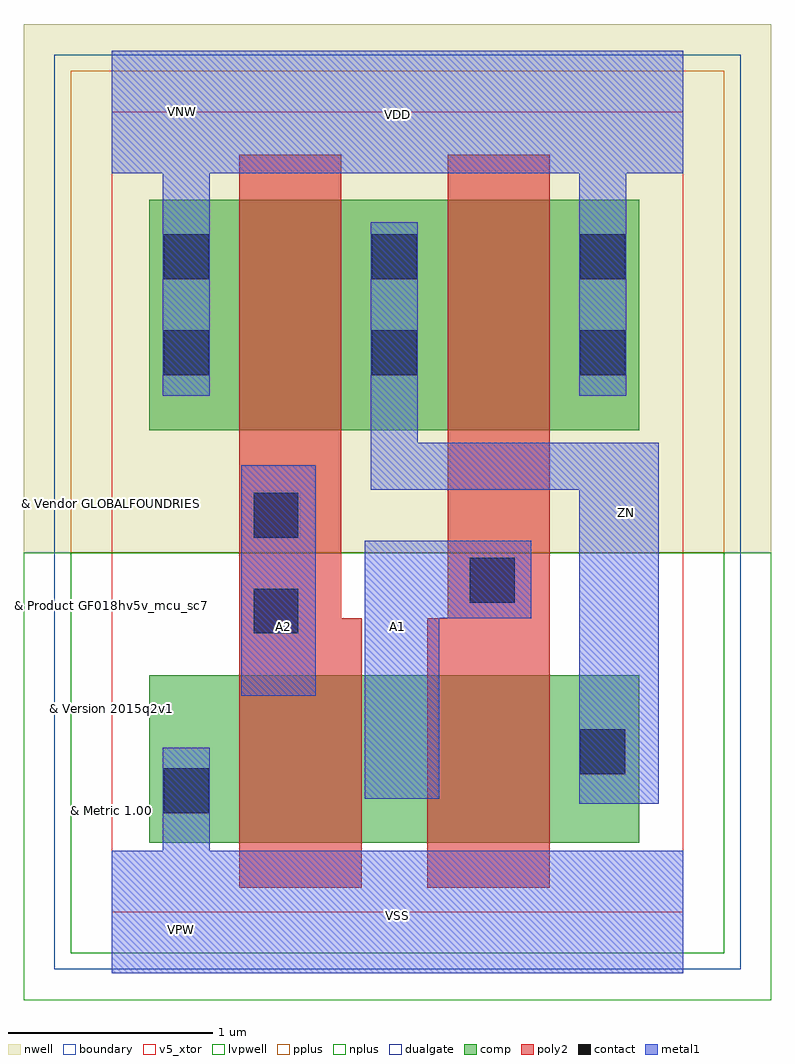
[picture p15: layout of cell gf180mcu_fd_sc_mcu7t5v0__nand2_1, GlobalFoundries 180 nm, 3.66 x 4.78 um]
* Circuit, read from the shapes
.subckt gf180mcu_fd_sc_mcu7t5v0__nand2_1 A1 A2 VDD VNW VSS ZN
XM1 n1 A2 VSS VSUBS nfet_05v0 w=0.82u l=0.6u
XM2 ZN A1 n1 VSUBS nfet_05v0 w=0.82u l=0.6u
XM3 ZN A2 VDD VNW pfet_05v0 w=1.13u l=0.5u
XM4 VDD A1 ZN VNW pfet_05v0 w=1.13u l=0.5u
.ends

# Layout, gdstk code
import gdstk
lib = gdstk.Library(unit=1e-6, precision=1e-09)
def R(c, l, rs):  # rectangles x0, y0, x1, y1
    for r in rs: c.add(gdstk.rectangle(r[:2], r[2:], *l))
def A(c, l, x, y, w, h, nx, ny, dx, dy):  # array of equal rectangles
    R(c, l, [(x+i*dx, y+j*dy, x+i*dx+w, y+j*dy+h) for i in range(nx) for j in range(ny)])
def P(c, l, *ps):  # polygons
    for p in ps: c.add(gdstk.Polygon(p, *l))
boundary = (0, 0)
nwell = (21, 0)
comp = (22, 0)
poly2 = (30, 0)
pplus = (31, 0)
nplus = (32, 0)
contact = (33, 0)
metal1 = (34, 0)
dualgate = (55, 0)
v5_xtor = (112, 1)
lvpwell = (204, 0)

gf180mcu_fd_sc_mcu7t5v0_ = lib.new_cell('gf180mcu_fd_sc_mcu7t5v0__nand2_1')
R(gf180mcu_fd_sc_mcu7t5v0_, boundary, [(0,0,2.8,3.92)])
R(gf180mcu_fd_sc_mcu7t5v0_, nwell, [(-0.43,1.76,3.23,4.35)])
R(gf180mcu_fd_sc_mcu7t5v0_, comp, [(0.185,0.34,2.585,1.16), (0.185,2.36,2.585,3.49)])
P(gf180mcu_fd_sc_mcu7t5v0_, poly2, [(0.625,0.12),(0.625,3.71),(1.125,3.71),(1.125,1.44),(1.225,1.44),(1.225,0.12)],
  [(1.545,0.12),(1.545,1.44),(1.645,1.44),(1.645,3.71),(2.145,3.71),(2.145,0.12)])
R(gf180mcu_fd_sc_mcu7t5v0_, pplus, [(-0.2,1.76,3,4.12)])
R(gf180mcu_fd_sc_mcu7t5v0_, nplus, [(-0.2,-0.2,3,1.76)])
A(gf180mcu_fd_sc_mcu7t5v0_, contact, 0.255, 2.63, 0.22, 0.22, 3, 2, 1.02, 0.47)
R(gf180mcu_fd_sc_mcu7t5v0_, contact, [(0.255,0.485,0.475,0.705), (2.295,0.675,2.515,0.895), (0.695,1.365,0.915,1.585), (1.755,1.515,1.975,1.735), (0.695,1.835,0.915,2.055)])
R(gf180mcu_fd_sc_mcu7t5v0_, metal1, [(0.635,1.06,1,2.19)])
P(gf180mcu_fd_sc_mcu7t5v0_, metal1, [(1.24,0.555),(1.24,1.82),(2.055,1.82),(2.055,1.44),(1.605,1.44),(1.605,0.555)],
  [(2.29,0.53),(2.29,2.07),(1.27,2.07),(1.27,3.38),(1.5,3.38),(1.5,2.3),(2.68,2.3),(2.68,0.53)],
  [(0,-0.3),(0,0.3),(0.25,0.3),(0.25,0.805),(0.48,0.805),(0.48,0.3),(2.8,0.3),(2.8,-0.3)],
  [(0.25,2.53),(0.25,3.62),(0,3.62),(0,4.22),(2.8,4.22),(2.8,3.62),(2.52,3.62),(2.52,2.53),(2.29,2.53),(2.29,3.62),(0.48,3.62),(0.48,2.53)])
R(gf180mcu_fd_sc_mcu7t5v0_, dualgate, [(-0.28,-0.28,3.08,4.2)])
R(gf180mcu_fd_sc_mcu7t5v0_, v5_xtor, [(0,0,2.8,3.92)])
R(gf180mcu_fd_sc_mcu7t5v0_, lvpwell, [(-0.43,-0.43,3.23,1.76)])
gf180mcu_fd_sc_mcu7t5v0_.add(gdstk.Label('VDD', (1.4,3.905), layer=34, texttype=10))
gf180mcu_fd_sc_mcu7t5v0_.add(gdstk.Label('VSS', (1.4,-0.015), layer=34, texttype=10))
gf180mcu_fd_sc_mcu7t5v0_.add(gdstk.Label('ZN', (2.52,1.96), layer=34, texttype=10))
gf180mcu_fd_sc_mcu7t5v0_.add(gdstk.Label('A1', (1.4,1.4), layer=34, texttype=10))
gf180mcu_fd_sc_mcu7t5v0_.add(gdstk.Label('A2', (0.84,1.4), layer=34, texttype=10))
gf180mcu_fd_sc_mcu7t5v0_.add(gdstk.Label('& Vendor GLOBALFOUNDRIES', (0,2), layer=63, texttype=63))
gf180mcu_fd_sc_mcu7t5v0_.add(gdstk.Label('& Product GF018hv5v_mcu_sc7', (0,1.5), layer=63, texttype=63))
gf180mcu_fd_sc_mcu7t5v0_.add(gdstk.Label('& Version 2015q2v1', (0,1), layer=63, texttype=63))
gf180mcu_fd_sc_mcu7t5v0_.add(gdstk.Label('& Metric 1.00', (0,0.5), layer=63, texttype=63))
gf180mcu_fd_sc_mcu7t5v0_.add(gdstk.Label('VNW', (0.345,3.92), layer=21, texttype=10))
gf180mcu_fd_sc_mcu7t5v0_.add(gdstk.Label('VPW', (0.34,-0.085), layer=204, texttype=10))

lib.write_gds('gf180mcu_fd_sc_mcu7t5v0__nand2_1.gds')
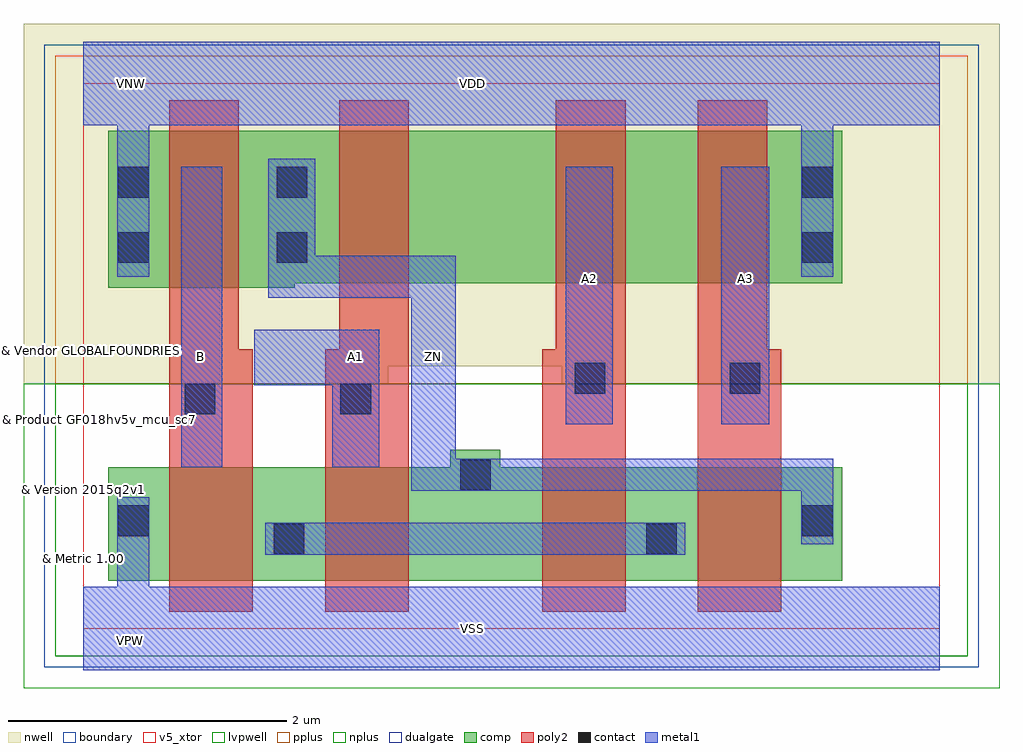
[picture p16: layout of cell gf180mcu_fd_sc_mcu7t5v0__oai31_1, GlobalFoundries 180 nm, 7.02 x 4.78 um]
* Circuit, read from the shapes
.subckt gf180mcu_fd_sc_mcu7t5v0__oai31_1 A1 A2 A3 B VDD VNW VSS ZN
XM1 n1 B VSS VSUBS nfet_05v0 w=0.815u l=0.6u
XM2 ZN A1 n1 VSUBS nfet_05v0 w=0.815u l=0.6u
XM3 n1 A2 ZN VSUBS nfet_05v0 w=0.815u l=0.6u
XM4 ZN A3 n1 VSUBS nfet_05v0 w=0.815u l=0.6u
XM5 ZN B VDD VNW pfet_05v0 w=1.13u l=0.5u
XM6 n2 A1 ZN VNW pfet_05v0 w=1.095u l=0.5u
XM7 n3 A2 n2 VNW pfet_05v0 w=1.095u l=0.5u
XM8 VDD A3 n3 VNW pfet_05v0 w=1.095u l=0.5u
.ends

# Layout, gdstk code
import gdstk
lib = gdstk.Library(unit=1e-6, precision=1e-09)
def R(c, l, rs):  # rectangles x0, y0, x1, y1
    for r in rs: c.add(gdstk.rectangle(r[:2], r[2:], *l))
def P(c, l, *ps):  # polygons
    for p in ps: c.add(gdstk.Polygon(p, *l))
boundary = (0, 0)
nwell = (21, 0)
comp = (22, 0)
poly2 = (30, 0)
pplus = (31, 0)
nplus = (32, 0)
contact = (33, 0)
metal1 = (34, 0)
dualgate = (55, 0)
v5_xtor = (112, 1)
lvpwell = (204, 0)

gf180mcu_fd_sc_mcu7t5v0_ = lib.new_cell('gf180mcu_fd_sc_mcu7t5v0__oai31_1')
R(gf180mcu_fd_sc_mcu7t5v0_, boundary, [(0,0,6.16,3.92)])
P(gf180mcu_fd_sc_mcu7t5v0_, nwell, [(-0.43,1.76),(-0.43,4.35),(6.59,4.35),(6.59,1.76),(3.44,1.76),(3.44,1.885),(2.195,1.885),(2.195,1.76)])
P(gf180mcu_fd_sc_mcu7t5v0_, comp, [(0.18,0.345),(0.18,1.16),(2.64,1.16),(2.64,1.285),(3,1.285),(3,1.16),(5.46,1.16),(5.46,0.345)],
  [(0.18,2.45),(0.18,3.58),(5.46,3.58),(5.46,2.485),(1.52,2.485),(1.52,2.45)])
P(gf180mcu_fd_sc_mcu7t5v0_, poly2, [(0.62,0.12),(0.62,3.8),(1.12,3.8),(1.12,2.01),(1.22,2.01),(1.22,0.12)],
  [(1.74,0.12),(1.74,2.01),(1.84,2.01),(1.84,3.8),(2.34,3.8),(2.34,0.12)],
  [(3.3,0.12),(3.3,2.01),(3.4,2.01),(3.4,3.8),(3.9,3.8),(3.9,0.12)],
  [(4.42,0.12),(4.42,3.8),(4.92,3.8),(4.92,2.01),(5.02,2.01),(5.02,0.12)])
R(gf180mcu_fd_sc_mcu7t5v0_, pplus, [(-0.2,1.76,6.36,4.12)])
R(gf180mcu_fd_sc_mcu7t5v0_, nplus, [(-0.2,-0.2,6.36,1.76)])
R(gf180mcu_fd_sc_mcu7t5v0_, contact, [(1.37,0.535,1.59,0.755), (4.05,0.535,4.27,0.755), (0.25,0.665,0.47,0.885), (5.17,0.665,5.39,0.885), (2.71,0.995,2.93,1.215), (0.73,1.54,0.95,1.76), (1.85,1.54,2.07,1.76), (3.535,1.69,3.755,1.91), (4.65,1.69,4.87,1.91), (0.25,2.63,0.47,2.85), (1.39,2.63,1.61,2.85), (5.17,2.63,5.39,2.85), (0.25,3.1,0.47,3.32), (1.39,3.1,1.61,3.32), (5.17,3.1,5.39,3.32)])
R(gf180mcu_fd_sc_mcu7t5v0_, metal1, [(1.31,0.53,4.33,0.76), (0.705,1.16,1,3.32), (3.47,1.47,3.81,3.32), (4.59,1.47,4.935,3.32)])
P(gf180mcu_fd_sc_mcu7t5v0_, metal1, [(1.79,1.16),(1.79,1.75),(1.23,1.75),(1.23,2.15),(2.13,2.15),(2.13,1.16)],
  [(5.165,0.605),(5.165,0.99),(2.36,0.99),(2.36,2.38),(1.33,2.38),(1.33,3.38),(1.67,3.38),(1.67,2.68),(2.68,2.68),(2.68,1.22),(5.395,1.22),(5.395,0.605)],
  [(0,-0.3),(0,0.3),(0.245,0.3),(0.245,0.945),(0.475,0.945),(0.475,0.3),(6.16,0.3),(6.16,-0.3)],
  [(0.245,2.53),(0.245,3.62),(0,3.62),(0,4.22),(6.16,4.22),(6.16,3.62),(5.395,3.62),(5.395,2.53),(5.165,2.53),(5.165,3.62),(0.475,3.62),(0.475,2.53)])
R(gf180mcu_fd_sc_mcu7t5v0_, dualgate, [(-0.28,-0.28,6.44,4.2)])
R(gf180mcu_fd_sc_mcu7t5v0_, v5_xtor, [(0,0,6.16,3.92)])
R(gf180mcu_fd_sc_mcu7t5v0_, lvpwell, [(-0.43,-0.43,6.59,1.76)])
gf180mcu_fd_sc_mcu7t5v0_.add(gdstk.Label('VDD', (2.8,3.92), layer=34, texttype=10))
gf180mcu_fd_sc_mcu7t5v0_.add(gdstk.Label('ZN', (2.52,1.96), layer=34, texttype=10))
gf180mcu_fd_sc_mcu7t5v0_.add(gdstk.Label('B', (0.84,1.96), layer=34, texttype=10))
gf180mcu_fd_sc_mcu7t5v0_.add(gdstk.Label('A1', (1.96,1.96), layer=34, texttype=10))
gf180mcu_fd_sc_mcu7t5v0_.add(gdstk.Label('A2', (3.64,2.52), layer=34, texttype=10))
gf180mcu_fd_sc_mcu7t5v0_.add(gdstk.Label('VSS', (2.8,0), layer=34, texttype=10))
gf180mcu_fd_sc_mcu7t5v0_.add(gdstk.Label('A3', (4.76,2.52), layer=34, texttype=10))
gf180mcu_fd_sc_mcu7t5v0_.add(gdstk.Label('& Vendor GLOBALFOUNDRIES', (0,2), layer=63, texttype=63))
gf180mcu_fd_sc_mcu7t5v0_.add(gdstk.Label('& Product GF018hv5v_mcu_sc7', (0,1.5), layer=63, texttype=63))
gf180mcu_fd_sc_mcu7t5v0_.add(gdstk.Label('& Version 2015q2v1', (0,1), layer=63, texttype=63))
gf180mcu_fd_sc_mcu7t5v0_.add(gdstk.Label('& Metric 1.00', (0,0.5), layer=63, texttype=63))
gf180mcu_fd_sc_mcu7t5v0_.add(gdstk.Label('VNW', (0.345,3.92), layer=21, texttype=10))
gf180mcu_fd_sc_mcu7t5v0_.add(gdstk.Label('VPW', (0.34,-0.085), layer=204, texttype=10))

lib.write_gds('gf180mcu_fd_sc_mcu7t5v0__oai31_1.gds')
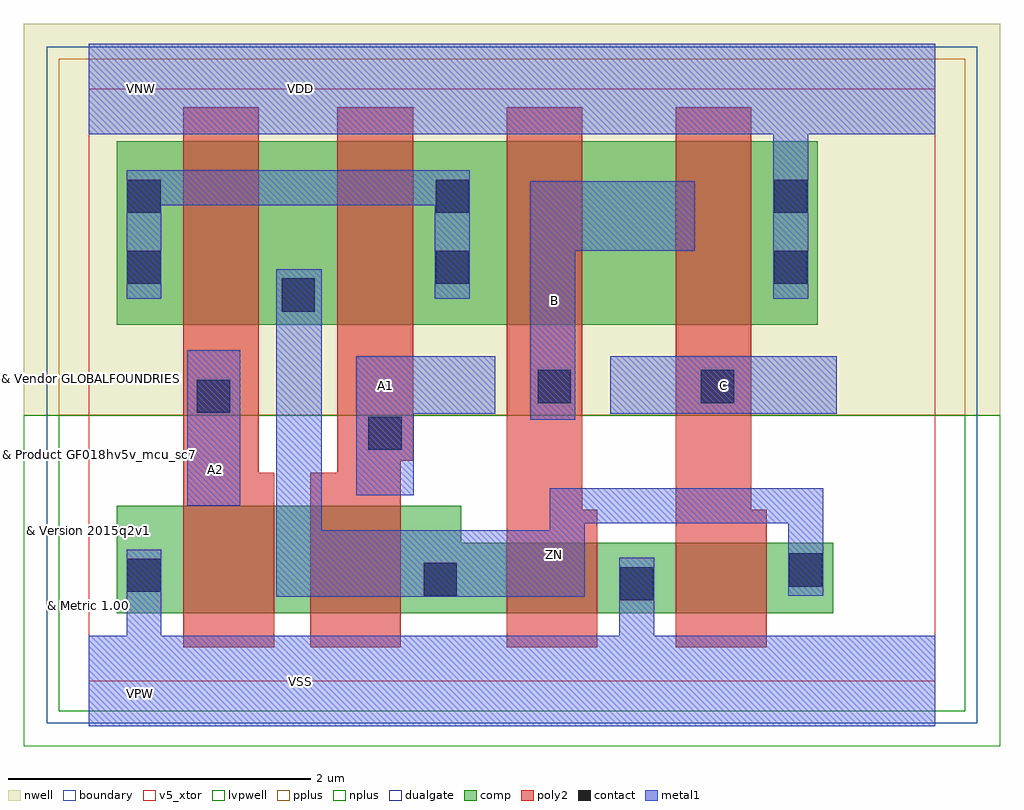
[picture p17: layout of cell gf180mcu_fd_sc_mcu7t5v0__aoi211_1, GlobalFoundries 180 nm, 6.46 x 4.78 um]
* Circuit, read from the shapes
.subckt gf180mcu_fd_sc_mcu7t5v0__aoi211_1 A1 A2 B C VDD VNW VSS ZN
XM1 n1 A2 VSS VSUBS nfet_05v0 w=0.71u l=0.6u
XM2 ZN A1 n1 VSUBS nfet_05v0 w=0.71u l=0.6u
XM3 VSS B ZN VSUBS nfet_05v0 w=0.465u l=0.6u
XM4 ZN C VSS VSUBS nfet_05v0 w=0.465u l=0.6u
XM5 ZN A2 n2 VNW pfet_05v0 w=1.215u l=0.5u
XM6 n2 A1 ZN VNW pfet_05v0 w=1.215u l=0.5u
XM7 n3 B n2 VNW pfet_05v0 w=1.215u l=0.5u
XM8 VDD C n3 VNW pfet_05v0 w=1.215u l=0.5u
.ends

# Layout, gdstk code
import gdstk
lib = gdstk.Library(unit=1e-6, precision=1e-09)
def R(c, l, rs):  # rectangles x0, y0, x1, y1
    for r in rs: c.add(gdstk.rectangle(r[:2], r[2:], *l))
def P(c, l, *ps):  # polygons
    for p in ps: c.add(gdstk.Polygon(p, *l))
boundary = (0, 0)
nwell = (21, 0)
comp = (22, 0)
poly2 = (30, 0)
pplus = (31, 0)
nplus = (32, 0)
contact = (33, 0)
metal1 = (34, 0)
dualgate = (55, 0)
v5_xtor = (112, 1)
lvpwell = (204, 0)

gf180mcu_fd_sc_mcu7t5v0_ = lib.new_cell('gf180mcu_fd_sc_mcu7t5v0__aoi211_1')
R(gf180mcu_fd_sc_mcu7t5v0_, boundary, [(0,0,5.6,3.92)])
R(gf180mcu_fd_sc_mcu7t5v0_, nwell, [(-0.43,1.76,6.03,4.35)])
R(gf180mcu_fd_sc_mcu7t5v0_, comp, [(0.185,2.36,4.825,3.575)])
P(gf180mcu_fd_sc_mcu7t5v0_, comp, [(0.185,0.45),(0.185,1.16),(2.465,1.16),(2.465,0.915),(4.925,0.915),(4.925,0.45)])
P(gf180mcu_fd_sc_mcu7t5v0_, poly2, [(0.625,0.225),(0.625,3.8),(1.125,3.8),(1.125,1.38),(1.225,1.38),(1.225,0.225)],
  [(1.465,0.225),(1.465,1.38),(1.645,1.38),(1.645,3.8),(2.145,3.8),(2.145,1.46),(2.065,1.46),(2.065,0.225)],
  [(2.765,0.225),(2.765,3.8),(3.265,3.8),(3.265,1.135),(3.365,1.135),(3.365,0.225)],
  [(3.885,0.225),(3.885,3.8),(4.385,3.8),(4.385,1.135),(4.485,1.135),(4.485,0.225)])
R(gf180mcu_fd_sc_mcu7t5v0_, pplus, [(-0.2,1.76,5.8,4.12)])
R(gf180mcu_fd_sc_mcu7t5v0_, nplus, [(-0.2,-0.2,5.8,1.76)])
R(gf180mcu_fd_sc_mcu7t5v0_, contact, [(3.515,0.535,3.735,0.755), (2.215,0.565,2.435,0.785), (0.255,0.59,0.475,0.81), (4.635,0.625,4.855,0.845), (1.85,1.53,2.07,1.75), (0.715,1.775,0.935,1.995), (2.97,1.84,3.19,2.06), (4.05,1.84,4.27,2.06), (1.275,2.445,1.495,2.665), (0.255,2.63,0.475,2.85), (2.295,2.63,2.515,2.85), (4.535,2.63,4.755,2.85), (0.255,3.1,0.475,3.32), (2.295,3.1,2.515,3.32), (4.535,3.1,4.755,3.32)])
R(gf180mcu_fd_sc_mcu7t5v0_, metal1, [(0.65,1.16,1,2.19), (3.45,1.77,4.95,2.15)])
P(gf180mcu_fd_sc_mcu7t5v0_, metal1, [(0.25,2.53),(0.25,3.38),(2.52,3.38),(2.52,2.53),(2.29,2.53),(2.29,3.15),(0.48,3.15),(0.48,2.53)],
  [(1.77,1.23),(1.77,2.15),(2.69,2.15),(2.69,1.77),(2.15,1.77),(2.15,1.23)],
  [(2.92,1.73),(2.92,3.31),(4.01,3.31),(4.01,2.85),(3.22,2.85),(3.22,1.73)],
  [(1.24,0.56),(1.24,2.725),(1.54,2.725),(1.54,1),(3.05,1),(3.05,1.275),(4.86,1.275),(4.86,0.565),(4.63,0.565),(4.63,1.045),(3.28,1.045),(3.28,0.56)],
  [(0,-0.3),(0,0.3),(0.25,0.3),(0.25,0.87),(0.48,0.87),(0.48,0.3),(3.51,0.3),(3.51,0.815),(3.74,0.815),(3.74,0.3),(5.6,0.3),(5.6,-0.3)],
  [(4.53,2.53),(4.53,3.62),(0,3.62),(0,4.22),(5.6,4.22),(5.6,3.62),(4.76,3.62),(4.76,2.53)])
R(gf180mcu_fd_sc_mcu7t5v0_, dualgate, [(-0.28,-0.28,5.88,4.2)])
R(gf180mcu_fd_sc_mcu7t5v0_, v5_xtor, [(0,0,5.6,3.92)])
R(gf180mcu_fd_sc_mcu7t5v0_, lvpwell, [(-0.43,-0.43,6.03,1.76)])
gf180mcu_fd_sc_mcu7t5v0_.add(gdstk.Label('B', (3.08,2.52), layer=34, texttype=10))
gf180mcu_fd_sc_mcu7t5v0_.add(gdstk.Label('C', (4.2,1.96), layer=34, texttype=10))
gf180mcu_fd_sc_mcu7t5v0_.add(gdstk.Label('VDD', (1.4,3.92), layer=34, texttype=10))
gf180mcu_fd_sc_mcu7t5v0_.add(gdstk.Label('VSS', (1.4,0), layer=34, texttype=10))
gf180mcu_fd_sc_mcu7t5v0_.add(gdstk.Label('ZN', (3.08,0.84), layer=34, texttype=10))
gf180mcu_fd_sc_mcu7t5v0_.add(gdstk.Label('A1', (1.96,1.96), layer=34, texttype=10))
gf180mcu_fd_sc_mcu7t5v0_.add(gdstk.Label('A2', (0.84,1.4), layer=34, texttype=10))
gf180mcu_fd_sc_mcu7t5v0_.add(gdstk.Label('& Vendor GLOBALFOUNDRIES', (0,2), layer=63, texttype=63))
gf180mcu_fd_sc_mcu7t5v0_.add(gdstk.Label('& Product GF018hv5v_mcu_sc7', (0,1.5), layer=63, texttype=63))
gf180mcu_fd_sc_mcu7t5v0_.add(gdstk.Label('& Version 2015q2v1', (0,1), layer=63, texttype=63))
gf180mcu_fd_sc_mcu7t5v0_.add(gdstk.Label('& Metric 1.00', (0,0.5), layer=63, texttype=63))
gf180mcu_fd_sc_mcu7t5v0_.add(gdstk.Label('VNW', (0.345,3.92), layer=21, texttype=10))
gf180mcu_fd_sc_mcu7t5v0_.add(gdstk.Label('VPW', (0.34,-0.085), layer=204, texttype=10))

lib.write_gds('gf180mcu_fd_sc_mcu7t5v0__aoi211_1.gds')
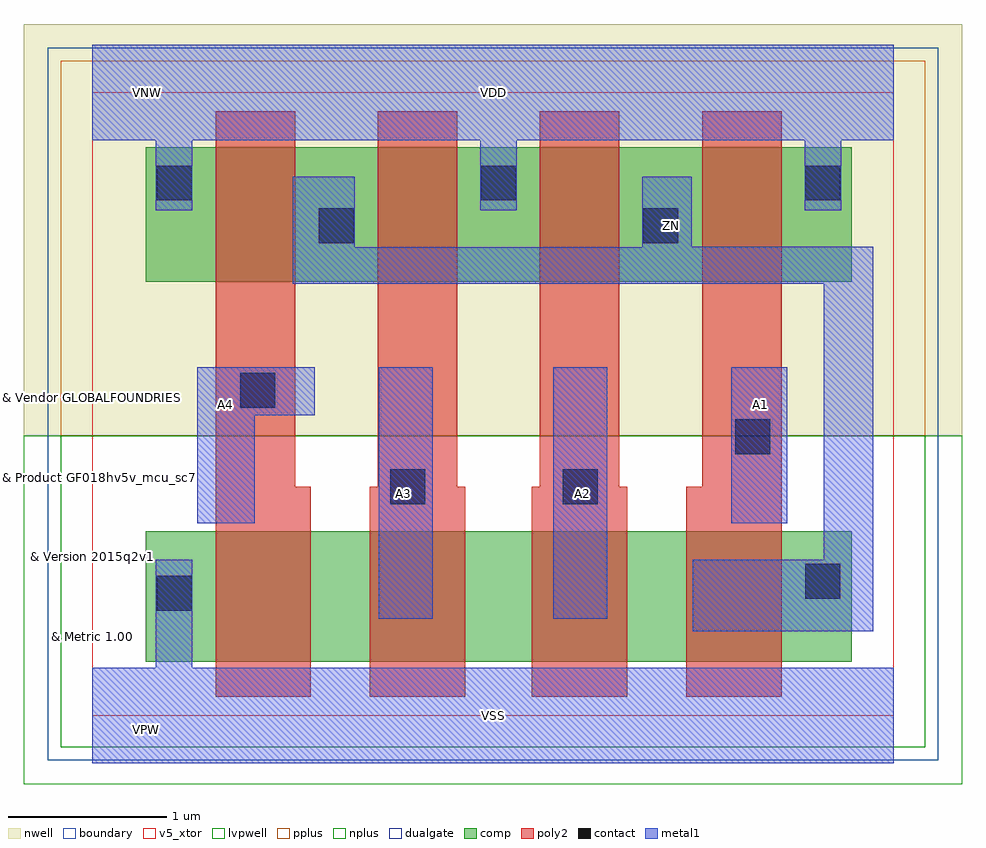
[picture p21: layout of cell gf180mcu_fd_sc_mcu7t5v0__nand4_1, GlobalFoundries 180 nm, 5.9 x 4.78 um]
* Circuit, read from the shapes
.subckt gf180mcu_fd_sc_mcu7t5v0__nand4_1 A1 A2 A3 A4 VDD VNW VSS ZN
XM1 n1 A4 VSS VSUBS nfet_05v0 w=0.82u l=0.6u
XM2 n2 A3 n1 VSUBS nfet_05v0 w=0.82u l=0.6u
XM3 n3 A2 n2 VSUBS nfet_05v0 w=0.82u l=0.6u
XM4 ZN A1 n3 VSUBS nfet_05v0 w=0.82u l=0.6u
XM5 ZN A4 VDD VNW pfet_05v0 w=0.845u l=0.5u
XM6 VDD A3 ZN VNW pfet_05v0 w=0.845u l=0.5u
XM7 ZN A2 VDD VNW pfet_05v0 w=0.845u l=0.5u
XM8 VDD A1 ZN VNW pfet_05v0 w=0.845u l=0.5u
.ends

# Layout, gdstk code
import gdstk
lib = gdstk.Library(unit=1e-6, precision=1e-09)
def R(c, l, rs):  # rectangles x0, y0, x1, y1
    for r in rs: c.add(gdstk.rectangle(r[:2], r[2:], *l))
def A(c, l, x, y, w, h, nx, ny, dx, dy):  # array of equal rectangles
    R(c, l, [(x+i*dx, y+j*dy, x+i*dx+w, y+j*dy+h) for i in range(nx) for j in range(ny)])
def P(c, l, *ps):  # polygons
    for p in ps: c.add(gdstk.Polygon(p, *l))
boundary = (0, 0)
nwell = (21, 0)
comp = (22, 0)
poly2 = (30, 0)
pplus = (31, 0)
nplus = (32, 0)
contact = (33, 0)
metal1 = (34, 0)
dualgate = (55, 0)
v5_xtor = (112, 1)
lvpwell = (204, 0)

gf180mcu_fd_sc_mcu7t5v0_ = lib.new_cell('gf180mcu_fd_sc_mcu7t5v0__nand4_1')
R(gf180mcu_fd_sc_mcu7t5v0_, boundary, [(0,0,5.04,3.92)])
R(gf180mcu_fd_sc_mcu7t5v0_, nwell, [(-0.43,1.76,5.47,4.35)])
R(gf180mcu_fd_sc_mcu7t5v0_, comp, [(0.335,0.34,4.775,1.16), (0.335,2.73,4.775,3.575)])
P(gf180mcu_fd_sc_mcu7t5v0_, poly2, [(0.775,0.12),(0.775,3.8),(1.275,3.8),(1.275,1.44),(1.375,1.44),(1.375,0.12)],
  [(1.745,0.12),(1.745,1.44),(1.795,1.44),(1.795,3.8),(2.295,3.8),(2.295,1.44),(2.345,1.44),(2.345,0.12)],
  [(2.765,0.12),(2.765,1.44),(2.815,1.44),(2.815,3.8),(3.315,3.8),(3.315,1.44),(3.365,1.44),(3.365,0.12)],
  [(3.735,0.12),(3.735,1.44),(3.835,1.44),(3.835,3.8),(4.335,3.8),(4.335,0.12)])
R(gf180mcu_fd_sc_mcu7t5v0_, pplus, [(-0.2,1.76,5.24,4.12)])
R(gf180mcu_fd_sc_mcu7t5v0_, nplus, [(-0.2,-0.2,5.24,1.76)])
A(gf180mcu_fd_sc_mcu7t5v0_, contact, 0.405, 3.24, 0.22, 0.22, 3, 1, 2.04, 0)
R(gf180mcu_fd_sc_mcu7t5v0_, contact, [(0.405,0.66,0.625,0.88), (4.485,0.735,4.705,0.955), (1.875,1.33,2.095,1.55), (2.96,1.33,3.18,1.55), (4.045,1.645,4.265,1.865), (0.93,1.935,1.15,2.155), (1.425,2.97,1.645,3.19), (3.465,2.97,3.685,3.19)])
R(gf180mcu_fd_sc_mcu7t5v0_, metal1, [(1.8,0.61,2.14,2.19), (2.9,0.61,3.24,2.19), (4.02,1.21,4.37,2.19)])
P(gf180mcu_fd_sc_mcu7t5v0_, metal1, [(0.66,1.21),(0.66,2.19),(1.4,2.19),(1.4,1.89),(1.02,1.89),(1.02,1.21)],
  [(3.775,0.53),(3.775,0.98),(4.6,0.98),(4.6,2.715),(1.26,2.715),(1.26,3.39),(1.65,3.39),(1.65,2.945),(3.46,2.945),(3.46,3.39),(3.77,3.39),(3.77,2.95),(4.91,2.95),(4.91,0.53)],
  [(0,-0.3),(0,0.3),(0.4,0.3),(0.4,0.98),(0.63,0.98),(0.63,0.3),(5.04,0.3),(5.04,-0.3)],
  [(0.4,3.18),(0.4,3.62),(0,3.62),(0,4.22),(5.04,4.22),(5.04,3.62),(4.71,3.62),(4.71,3.18),(4.48,3.18),(4.48,3.62),(2.67,3.62),(2.67,3.18),(2.44,3.18),(2.44,3.62),(0.63,3.62),(0.63,3.18)])
R(gf180mcu_fd_sc_mcu7t5v0_, dualgate, [(-0.28,-0.28,5.32,4.2)])
R(gf180mcu_fd_sc_mcu7t5v0_, v5_xtor, [(0,0,5.04,3.92)])
R(gf180mcu_fd_sc_mcu7t5v0_, lvpwell, [(-0.43,-0.43,5.47,1.76)])
gf180mcu_fd_sc_mcu7t5v0_.add(gdstk.Label('A3', (1.96,1.4), layer=34, texttype=10))
gf180mcu_fd_sc_mcu7t5v0_.add(gdstk.Label('A4', (0.84,1.96), layer=34, texttype=10))
gf180mcu_fd_sc_mcu7t5v0_.add(gdstk.Label('VDD', (2.52,3.92), layer=34, texttype=10))
gf180mcu_fd_sc_mcu7t5v0_.add(gdstk.Label('VSS', (2.52,0), layer=34, texttype=10))
gf180mcu_fd_sc_mcu7t5v0_.add(gdstk.Label('ZN', (3.64,3.08), layer=34, texttype=10))
gf180mcu_fd_sc_mcu7t5v0_.add(gdstk.Label('A1', (4.2,1.96), layer=34, texttype=10))
gf180mcu_fd_sc_mcu7t5v0_.add(gdstk.Label('A2', (3.08,1.4), layer=34, texttype=10))
gf180mcu_fd_sc_mcu7t5v0_.add(gdstk.Label('& Vendor GLOBALFOUNDRIES', (0,2), layer=63, texttype=63))
gf180mcu_fd_sc_mcu7t5v0_.add(gdstk.Label('& Product GF018hv5v_mcu_sc7', (0,1.5), layer=63, texttype=63))
gf180mcu_fd_sc_mcu7t5v0_.add(gdstk.Label('& Version 2015q2v1', (0,1), layer=63, texttype=63))
gf180mcu_fd_sc_mcu7t5v0_.add(gdstk.Label('& Metric 1.00', (0,0.5), layer=63, texttype=63))
gf180mcu_fd_sc_mcu7t5v0_.add(gdstk.Label('VNW', (0.345,3.92), layer=21, texttype=10))
gf180mcu_fd_sc_mcu7t5v0_.add(gdstk.Label('VPW', (0.34,-0.085), layer=204, texttype=10))

lib.write_gds('gf180mcu_fd_sc_mcu7t5v0__nand4_1.gds')
